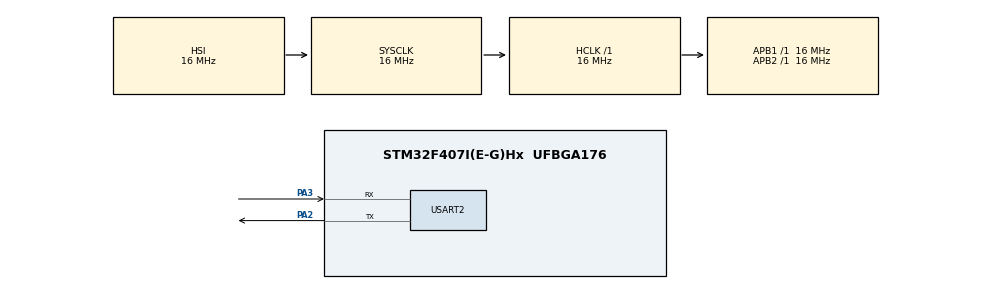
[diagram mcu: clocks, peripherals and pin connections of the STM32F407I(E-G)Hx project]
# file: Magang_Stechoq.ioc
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Mcu.Family=STM32F4
Mcu.Name=STM32F407I(E-G)Hx
Mcu.Package=UFBGA176
NVIC.PriorityGroup=NVIC_PRIORITYGROUP_4
NVIC.USART2_IRQn=true\:0\:0\:false\:false\:true\:true\:true\:true
PA2.Mode=Asynchronous
PA2.Signal=USART2_TX
PA3.Mode=Asynchronous
PA3.Signal=USART2_RX
ProjectManager.HeapSize=0x200
ProjectManager.StackSize=0x400
ProjectManager.TargetToolchain=STM32CubeIDE
RCC.AHBFreq_Value=16000000
RCC.APB1Freq_Value=16000000
RCC.APB2Freq_Value=16000000
RCC.CortexFreq_Value=16000000
RCC.HSE_VALUE=25000000
RCC.HSI_VALUE=16000000
RCC.LSE_VALUE=32768
RCC.SYSCLKFreq_VALUE=16000000
RCC.VCOOutputFreq_Value=192000000
USART2.VirtualMode=VM_ASYNC
board=custom

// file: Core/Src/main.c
/* USER CODE BEGIN Header */
/**
  ******************************************************************************
  * @file    main.c
  * @brief   APP1: Button cycles 1 LED, UART2 cmd PING/HELLO/ENTER_BL (RX interrupt)
  ******************************************************************************
  */
/* USER CODE END Header */

#include "main.h"
#include <stdio.h>
#include <string.h>

/* ===== USART2 handle ===== */
UART_HandleTypeDef huart2;

/* ===== Magic flag in RAM (.noinit) ===== */
__attribute__((section(".noinit"))) volatile uint32_t boot_magic;
#define BOOT_MAGIC 0xB00710ADUL

/* ===== UART RX state ===== */
static volatile uint8_t  rxByte;
static volatile uint8_t  lineReady = 0;
static volatile uint16_t rxIdx = 0;
static char rxLine[128];

/* ===== Redirect printf -> USART2 ===== */
int __io_putchar(int ch)
{
  HAL_UART_Transmit(&huart2, (uint8_t*)&ch, 1, 100);
  return ch;
}

/* ===== Prototypes ===== */
void SystemClock_Config(void);
static void MX_GPIO_Init(void);
static void MX_USART2_UART_Init(void);
void Error_Handler(void);

/* ===== LED helpers (PD12..PD15) ===== */
static void leds_all_off(void)
{
  HAL_GPIO_WritePin(GPIOD, GPIO_PIN_12|GPIO_PIN_13|GPIO_PIN_14|GPIO_PIN_15, GPIO_PIN_RESET);
}

static void set_single_led(uint8_t idx)
{
  leds_all_off();
  switch (idx & 3)
  {
    case 0: HAL_GPIO_WritePin(GPIOD, GPIO_PIN_12, GPIO_PIN_SET); break; // Green
    case 1: HAL_GPIO_WritePin(GPIOD, GPIO_PIN_13, GPIO_PIN_SET); break; // Orange
    case 2: HAL_GPIO_WritePin(GPIOD, GPIO_PIN_14, GPIO_PIN_SET); break; // Red
    case 3: HAL_GPIO_WritePin(GPIOD, GPIO_PIN_15, GPIO_PIN_SET); break; // Blue
  }
}

/* ===== UART RX callbacks (INTERRUPT) ===== */
void HAL_UART_RxCpltCallback(UART_HandleTypeDef *huart)
{
  if (huart->Instance != USART2) return;

  char c = (char)rxByte;

  if (c == '\r') {
    // ignore
  } else if (c == '\n') {
    if (rxIdx > 0) {
      rxLine[rxIdx] = 0;
      lineReady = 1;
      rxIdx = 0;
    }
  } else {
    if (rxIdx < sizeof(rxLine) - 1) rxLine[rxIdx++] = c;
    else rxIdx = 0;
  }

  /* re-arm receive 1 byte */
  HAL_UART_Receive_IT(&huart2, (uint8_t*)&rxByte, 1);
}

void HAL_UART_ErrorCallback(UART_HandleTypeDef *huart)
{
  if (huart->Instance != USART2) return;

  /* Clear overrun & re-arm */
  __HAL_UART_CLEAR_OREFLAG(huart);
  HAL_UART_Receive_IT(&huart2, (uint8_t*)&rxByte, 1);
}

/* ===== MAIN ===== */
int main(void)
{
  HAL_Init();
  SystemClock_Config();
  MX_GPIO_Init();
  MX_USART2_UART_Init();

  /* start RX interrupt */
  HAL_UART_Receive_IT(&huart2, (uint8_t*)&rxByte, 1);

  printf("APP_VER: 1\r\n");
  printf("APP_READY\r\n");

  uint8_t led_idx = 0;
  set_single_led(led_idx);

  while (1)
  {
    /* ===== Button USER PA0: cycle 1 LED ===== */
    if (HAL_GPIO_ReadPin(GPIOA, GPIO_PIN_0) == GPIO_PIN_SET)
    {
      led_idx = (led_idx + 1) & 3;
      set_single_led(led_idx);
      printf("BTN: LED_IDX=%u\r\n", led_idx);

      HAL_Delay(200);
      while (HAL_GPIO_ReadPin(GPIOA, GPIO_PIN_0) == GPIO_PIN_SET) {}
      HAL_Delay(50);
    }

    /* ===== process UART line ===== */
    if (lineReady)
    {
      lineReady = 0;

      char line[128];
      strncpy(line, rxLine, sizeof(line));
      line[sizeof(line) - 1] = 0;

      printf("RX: %s\r\n", line);

      if (strcmp(line, "PING") == 0) {
        printf("PONG\r\n");
      } else if (strcmp(line, "HELLO") == 0) {
        printf("HI FROM STM32\r\n");
      } else if (strcmp(line, "ENTER_BL") == 0) {
        printf("OK: ENTER_BL\r\n");
        boot_magic = BOOT_MAGIC;
        HAL_Delay(10);
        NVIC_SystemReset();
      } else {
        printf("UNKNOWN\r\n");
      }
    }

    HAL_Delay(1);
  }
}

/* ===== Clock: HSI 16MHz (simple) ===== */
void SystemClock_Config(void)
{
  RCC_OscInitTypeDef RCC_OscInitStruct = {0};
  RCC_ClkInitTypeDef RCC_ClkInitStruct = {0};

  __HAL_RCC_PWR_CLK_ENABLE();
  __HAL_PWR_VOLTAGESCALING_CONFIG(PWR_REGULATOR_VOLTAGE_SCALE1);

  RCC_OscInitStruct.OscillatorType = RCC_OSCILLATORTYPE_HSI;
  RCC_OscInitStruct.HSIState = RCC_HSI_ON;
  RCC_OscInitStruct.HSICalibrationValue = RCC_HSICALIBRATION_DEFAULT;
  RCC_OscInitStruct.PLL.PLLState = RCC_PLL_NONE;
  if (HAL_RCC_OscConfig(&RCC_OscInitStruct) != HAL_OK) Error_Handler();

  RCC_ClkInitStruct.ClockType = RCC_CLOCKTYPE_HCLK|RCC_CLOCKTYPE_SYSCLK
                              |RCC_CLOCKTYPE_PCLK1|RCC_CLOCKTYPE_PCLK2;
  RCC_ClkInitStruct.SYSCLKSource = RCC_SYSCLKSOURCE_HSI;
  RCC_ClkInitStruct.AHBCLKDivider = RCC_SYSCLK_DIV1;
  RCC_ClkInitStruct.APB1CLKDivider = RCC_HCLK_DIV1;
  RCC_ClkInitStruct.APB2CLKDivider = RCC_HCLK_DIV1;

  if (HAL_RCC_ClockConfig(&RCC_ClkInitStruct, FLASH_LATENCY_0) != HAL_OK) Error_Handler();
}

/* ===== USART2: 115200 8N1 (PA2/PA3) ===== */
static void MX_USART2_UART_Init(void)
{
  __HAL_RCC_USART2_CLK_ENABLE();

  huart2.Instance = USART2;
  huart2.Init.BaudRate = 115200;
  huart2.Init.WordLength = UART_WORDLENGTH_8B;
  huart2.Init.StopBits = UART_STOPBITS_1;
  huart2.Init.Parity = UART_PARITY_NONE;
  huart2.Init.Mode = UART_MODE_TX_RX;
  huart2.Init.HwFlowCtl = UART_HWCONTROL_NONE;
  huart2.Init.OverSampling = UART_OVERSAMPLING_16;

  if (HAL_UART_Init(&huart2) != HAL_OK) Error_Handler();

  /* Enable USART2 IRQ (biar RxCpltCallback jalan) */
  HAL_NVIC_SetPriority(USART2_IRQn, 5, 0);
  HAL_NVIC_EnableIRQ(USART2_IRQn);
}

/* ===== GPIO: PA0 button, PD12..PD15 LEDs, PA2/PA3 AF7 ===== */
static void MX_GPIO_Init(void)
{
  GPIO_InitTypeDef GPIO_InitStruct = {0};

  __HAL_RCC_GPIOA_CLK_ENABLE();
  __HAL_RCC_GPIOD_CLK_ENABLE();

  /* PA0 USER button */
  GPIO_InitStruct.Pin = GPIO_PIN_0;
  GPIO_InitStruct.Mode = GPIO_MODE_INPUT;
  GPIO_InitStruct.Pull = GPIO_NOPULL;
  HAL_GPIO_Init(GPIOA, &GPIO_InitStruct);

  /* PD12..PD15 LEDs */
  GPIO_InitStruct.Pin = GPIO_PIN_12|GPIO_PIN_13|GPIO_PIN_14|GPIO_PIN_15;
  GPIO_InitStruct.Mode = GPIO_MODE_OUTPUT_PP;
  GPIO_InitStruct.Pull = GPIO_NOPULL;
  GPIO_InitStruct.Speed = GPIO_SPEED_FREQ_LOW;
  HAL_GPIO_Init(GPIOD, &GPIO_InitStruct);
  leds_all_off();

  /* PA2/PA3 USART2 pins */
  GPIO_InitStruct.Pin = GPIO_PIN_2|GPIO_PIN_3;
  GPIO_InitStruct.Mode = GPIO_MODE_AF_PP;
  GPIO_InitStruct.Pull = GPIO_PULLUP;
  GPIO_InitStruct.Speed = GPIO_SPEED_FREQ_VERY_HIGH;
  GPIO_InitStruct.Alternate = GPIO_AF7_USART2;
  HAL_GPIO_Init(GPIOA, &GPIO_InitStruct);
}

void Error_Handler(void)
{
  __disable_irq();
  while (1) {}
}
